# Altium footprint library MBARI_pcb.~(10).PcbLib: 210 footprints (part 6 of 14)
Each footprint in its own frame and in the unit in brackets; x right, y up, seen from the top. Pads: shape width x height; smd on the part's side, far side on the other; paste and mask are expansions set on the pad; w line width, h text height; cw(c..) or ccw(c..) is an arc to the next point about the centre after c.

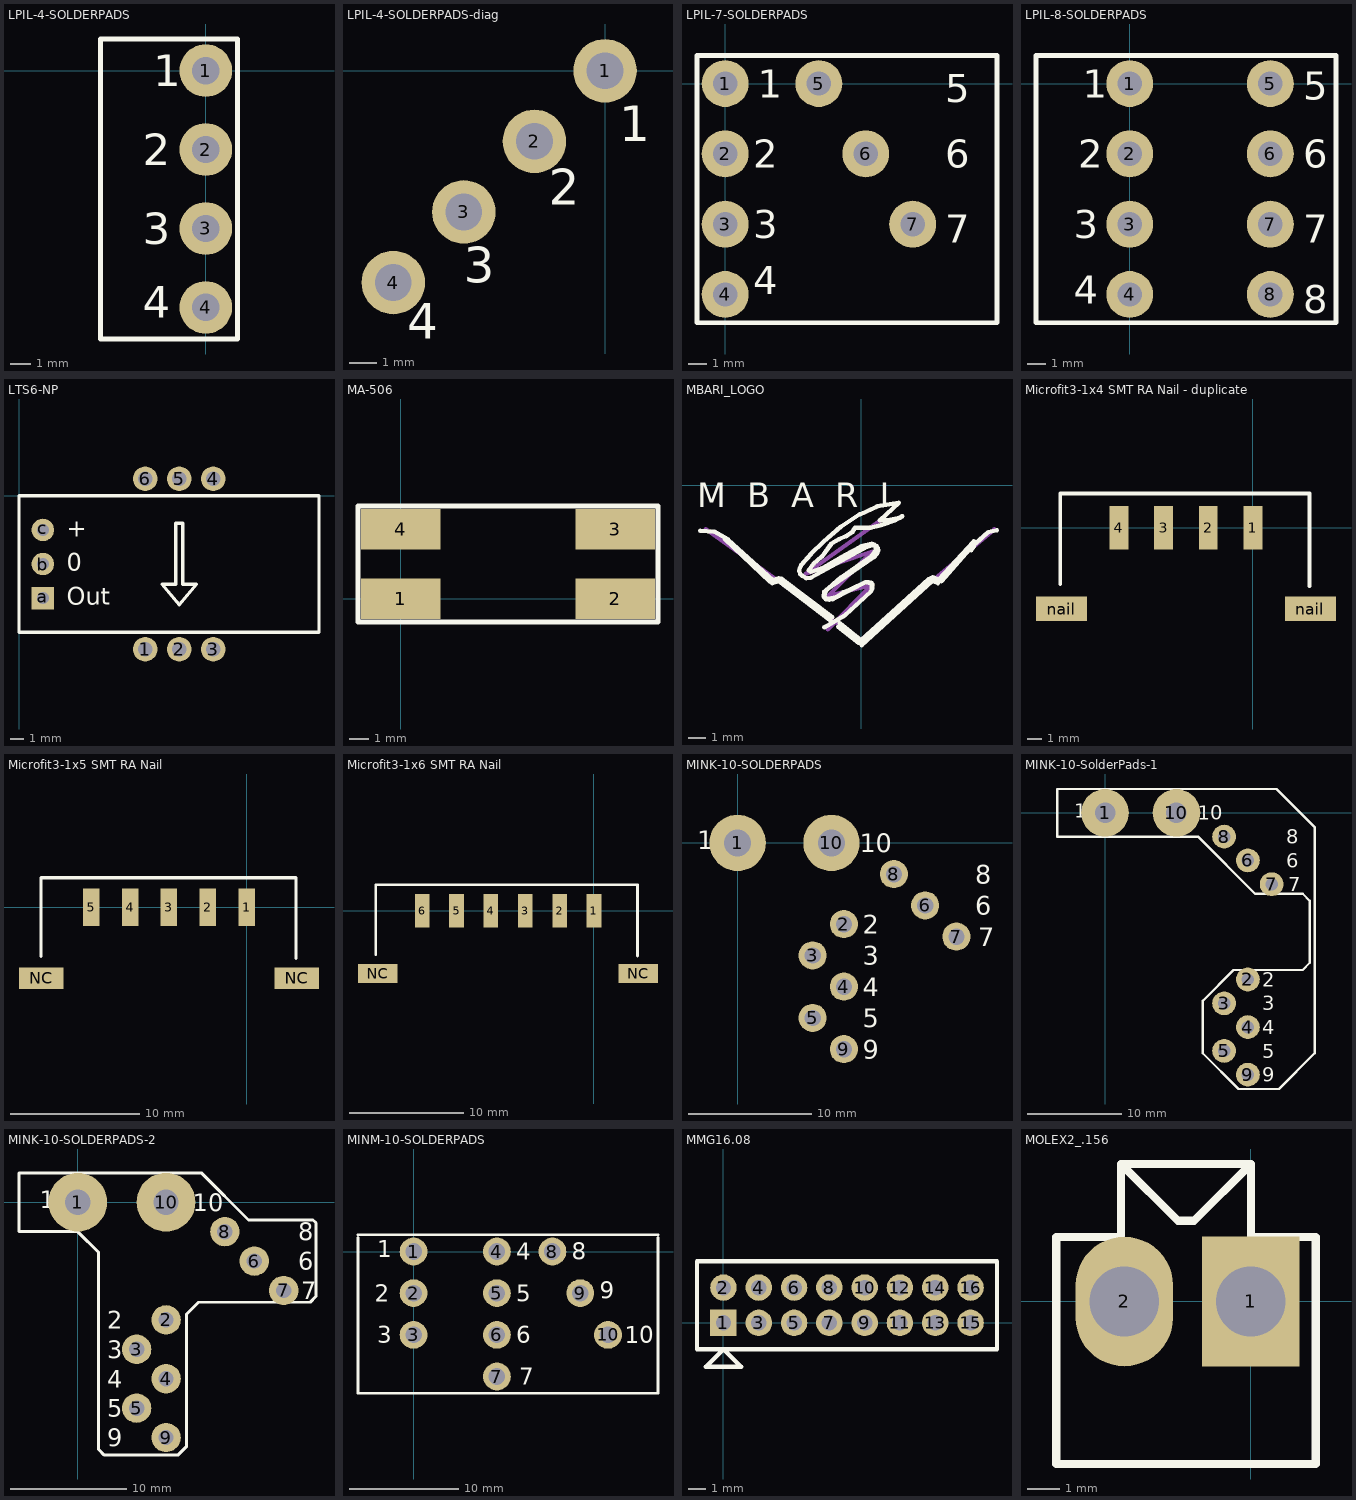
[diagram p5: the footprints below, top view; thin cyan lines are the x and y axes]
## LPIL-4-SOLDERPADS [mil]
pads (4):
  round 100 hole 52: 1(0,0) 2(0,-150) 3(0,-300) 4(0,-450)
TopOverlay:
  lines w10: -200,-510 -200,60 60,60 60,-510 -200,-510
  text "4" at -120,-470 h60
  text "3" at -120,-330 h60
  text "2" at -120,-180 h60
  text "1" at -100,-30 h60

## LPIL-4-SOLDERPADS-diag [mil]
pads (4):
  round 90 hole 52: 1(0,0) 2(-100,-100) 3(-200,-200) 4(-300,-300)
TopOverlay:
  text "1" at 20,-100 h50
  text "2" at -80,-190 h50
  text "3" at -200,-300 h50
  text "4" at -280,-380 h50

## LPIL-7-SOLDERPADS [mil]
pads (7):
  round 100 hole 52: 1(0,0) 2(0,-150) 3(0,-300) 4(0,-450) 5(200,0) 6(300,-150) 7(400,-300)
TopOverlay:
  lines w10: -60,-510 580,-510 580,60 -60,60 -60,-510
  text "7" at 470,-340 h60
  text "6" at 470,-180 h60
  text "5" at 470,-40 h60
  text "4" at 60,-450 h60
  text "3" at 60,-330 h60
  text "2" at 60,-180 h60
  text "1" at 70,-30 h60

## LPIL-8-SOLDERPADS [mil]
pads (8):
  round 100 hole 52: 1(0,0) 2(0,-150) 3(0,-300) 4(0,-450) 5(300,0) 6(300,-150) 7(300,-300) 8(300,-450)
TopOverlay:
  lines w10: -200,-510 -200,60 440,60 440,-510 -200,-510
  text "1" at -100,-30 h60
  text "2" at -110,-180 h60
  text "3" at -120,-330 h60
  text "4" at -120,-470 h60
  text "5" at 370,-35 h60
  text "6" at 370,-180 h60
  text "7" at 370,-340 h60
  text "8" at 370,-490 h60

## LTS6-NP [mil]
pads (9):
  round 72 hole 42: 1(370,-450) 2(470,-450) 3(570,-450) 4(570,50) 5(470,50) 6(370,50)
  rect 66x66 hole 35: a(70,-300)
  round 66 hole 35: b(70,-200) c(70,-100)
TopOverlay:
  lines w10: 0,-400 880,-400 880,0 0,0 0,-400 ; 420,-260 470,-320 520,-260 480,-260 480,-80 460,-80 460,-260 420,-260
  text "+" at 140,-120 h51
  text "0" at 140,-220 h51
  text "Out" at 140,-320 h51

## MA-506 [mm] "Epson Quartz Crystal"
height 4.572
pads (4):
  rect 4.1x2.1 smd: 1(0,0) 2(11.1,0) 3(11.1,3.6) 4(0,3.6)
TopOverlay:
  lines w0.254: -2.2,-1.2 -2.2,4.8 13.3,4.8 13.3,-1.2 -2.2,-1.2

## MBARI_LOGO [mil]
TopOverlay:
  lines w10: -363,-103 -331,-105 -300,-123 -199,-214 -186,-210 -179,-211 -65,-298 ; -308,-121 -205,-218 ; -200,-221 -185,-217 -70,-305 ; -83,-321 -37,-294 22,-240 25,-233 25,-223 23,-220 17,-219 10,-219 ; -52,-319 -5,-356 ; -48,-312 0,-350 152,-212 161,-208 175,-213 254,-127 257,-132 286,-106 306,-102 ; 24,-234 24,-226 22,-222 17,-220 10,-219 ; 158,-216 173,-221 ; 180,-217 245,-144 ; 248,-147 254,-138 ; 10,-219 3,-222 -40,-242 -57,-253 -80,-257 -84,-252 -83,-240 -45,-208 23,-161 34,-145 30,-134 24,-132 0,-138 -36,-158 -84,-186 -114,-196 -118,-192 -107,-177 -89,-162 -67,-132 -49,-122 -34,-115 -21,-107 -14,-96 21,-96 44,-91 60,-85 76,-80 93,-70 88,-74 59,-79 42,-79 85,-40 36,-48 -3,-66 -46,-94 -85,-128 -113,-155 -135,-180 -139,-188 -140,-194 -137,-201 -132,-205 -124,-210 -114,-209 14,-139 24,-136 31,-136 35,-138 37,-142 39,-147 36,-154 28,-163 -67,-228 -78,-236 -82,-244 -83,-250 -79,-257 -72,-259 -64,-257 10,-219 ; 1,-361 160,-216 1,-361
  text "M  B  A  R  I" at -370,-50 h55
Mechanical3:
  lines w10: -350,-100 0,-350 300,-100 ; -75,-325 25,-225 -75,-250 25,-150 -125,-200 50,-75

## Microfit3-1x4 SMT RA Nail - duplicate [mil] "Microfit 3 Single Row 4 Position SMT Right Angle Nail"
pads (6):
  rect 50x115 smd: 1(0,0) 2(-118.11,0) 3(-236.22,0) 4(-354.33,0)
  rect 135x65 smd: nail(-506.5,-215.5) nail(152.5,-215.5)
TopOverlay:
  lines w10: -510,-150 -510,90 150,90 150,-155

## Microfit3-1x5 SMT RA Nail [mil] "Microfit 3.0 Single Row SMT with Nails 5 Position"
pads (7):
  rect 50x115 smd: 1(0,0) 2(-118.11,0) 3(-236.22,0) 4(-354.33,0) 5(-472.44,0)
  rect 135x65 smd: NC(-624.5,-215.5) NC(152.5,-215.5)
TopOverlay:
  lines w10: -625,-150 -625,90 150,90 150,-155

## Microfit3-1x6 SMT RA Nail [mil] "Microfit 3 Single Row 6 Position SMT Right Angle Nail"
pads (8):
  rect 50x115 smd: 1(0,0) 2(-118.11,0) 3(-236.22,0) 4(-354.33,0) 5(-472.44,0) 6(-590.55,0)
  rect 135x65 smd: NC(-743.5,-215.5) NC(152.5,-215.5)
TopOverlay:
  lines w10: -750,-150 -750,90 150,90 150,-155

## MINK-10-SOLDERPADS [mil]
pads (10):
  round 180 hole 86: 1(0,0) 10(300,0)
  round 90 hole 52: 2(340,-260) 3(240,-360) 4(340,-460) 5(240,-560) 6(600,-200) 7(700,-300) 8(500,-100) 9(340,-660)
TopOverlay:
  text "1" at -130,-20 h60
  text "2" at 400,-290 h60
  text "3" at 400,-390 h60
  text "10" at 390,-30 h60
  text "4" at 400,-490 h60
  text "5" at 400,-590 h60
  text "6" at 760,-230 h60
  text "7" at 770,-330 h60
  text "8" at 760,-130 h60
  text "9" at 400,-690 h60

## MINK-10-SolderPads-1 [mil]
pads (10):
  round 200 hole 86: 1(0,0) 10(300,0)
  round 100 hole 52: 2(600,-700) 3(500,-800) 4(600,-900) 5(500,-1000) 6(600,-200) 7(700,-300) 8(500,-100) 9(600,-1100)
TopOverlay:
  lines w10: -200,-100 390,-100 630,-340 830,-340 860,-370 860,-630 830,-660 540,-660 410,-790 410,-1010 560,-1160 730,-1160 880,-1010 880,-60 720,100 -200,100 -200,-100
  text "1" at -130,-20 h60
  text "2" at 660,-730 h60
  text "3" at 660,-830 h60
  text "10" at 390,-30 h60
  text "4" at 660,-930 h60
  text "5" at 660,-1030 h60
  text "6" at 760,-230 h60
  text "7" at 770,-330 h60
  text "8" at 760,-130 h60
  text "9" at 660,-1130 h60

## MINK-10-SOLDERPADS-2 [mil]
pads (10):
  round 200 hole 86: 1(0,0) 10(300,0)
  round 100 hole 52: 2(300,-400) 3(200,-500) 4(300,-600) 5(200,-700) 6(600,-200) 7(700,-300) 8(500,-100) 9(300,-800)
TopOverlay:
  lines w10: -200,-100 0,-100 70,-170 70,-840 90,-860 340,-860 370,-830 370,-380 410,-340 790,-340 810,-320 810,-70 800,-60 580,-60 420,100 -200,100 -200,-100
  text "9" at 100,-830 h60
  text "8" at 750,-130 h60
  text "7" at 760,-330 h60
  text "6" at 750,-230 h60
  text "5" at 100,-730 h60
  text "4" at 100,-630 h60
  text "10" at 390,-30 h60
  text "3" at 100,-530 h60
  text "2" at 100,-430 h60
  text "1" at -130,-20 h60

## MINM-10-SOLDERPADS [mil] "MIN-M 10/16AWG holes"
pads (10):
  round 100 hole 59.5: 1(0,0) 2(0,-150) 3(0,-300) 4(300,0) 5(300,-150) 6(300,-300) 7(300,-450) 8(500,0) 9(600,-150) 10(700,-300)
TopOverlay:
  lines w10: -200,50 -200,-510 880,-510 880,50 ; -200,60 880,60
  text "1" at -130,-20 h60
  text "2" at -140,-180 h60
  text "3" at -130,-330 h60
  text "10" at 760,-330 h60
  text "4" at 370,-30 h60
  text "5" at 370,-180 h60
  text "6" at 370,-330 h60
  text "7" at 380,-480 h60
  text "8" at 570,-30 h60
  text "9" at 670,-170 h60

## MMG16.08 [mil]
pads (16):
  rect 60x60 hole 35: 1(0,0)
  round 60 hole 35: 2(0,80) 3(80,0) 4(80,80) 5(160,0) 6(160,80) 7(240,0) 8(240,80) 9(320,0) 10(320,80) 11(400,0) 12(400,80) 13(480,0) 14(480,80) 15(560,0) 16(560,80)
TopOverlay:
  lines w10: -60,-60 -60,140 620,140 620,-60 -60,-60 ; -40,-100 0,-60 40,-100 -40,-100

## MOLEX2_.156 [mil]
pads (2):
  rect 120x160 hole 86: 1(0,0)
  oval 120x160 hole 86: 2(-156,0)
TopOverlay:
  lines w10: -160,169.57 0,169.57 ; -160,169.57 -160,79.57 -240,79.57 -240,-200.43 80,-200.43 80,79.57 0,79.57 0,169.57 ; -160,169.57 -90,99.57 -70,99.57 0,169.57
